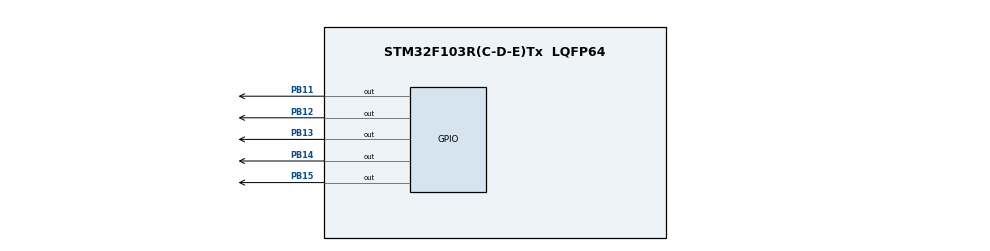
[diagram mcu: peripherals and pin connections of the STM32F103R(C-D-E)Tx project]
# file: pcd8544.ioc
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Mcu.Family=STM32F1
Mcu.Name=STM32F103R(C-D-E)Tx
Mcu.Package=LQFP64
NVIC.PriorityGroup=NVIC_PRIORITYGROUP_4
PB11.GPIO_Speed=GPIO_SPEED_FREQ_HIGH
PB11.Signal=GPIO_Output
PB12.GPIO_Speed=GPIO_SPEED_FREQ_HIGH
PB12.Signal=GPIO_Output
PB13.GPIO_Speed=GPIO_SPEED_FREQ_HIGH
PB13.Signal=GPIO_Output
PB14.GPIO_Speed=GPIO_SPEED_FREQ_HIGH
PB14.Signal=GPIO_Output
PB15.GPIO_Speed=GPIO_SPEED_FREQ_HIGH
PB15.Signal=GPIO_Output
ProjectManager.HeapSize=0x200
ProjectManager.StackSize=0x400
ProjectManager.TargetToolchain=EWARM
RCC.APB1Freq_Value=8000000
RCC.APB2Freq_Value=8000000
board=pcd8544

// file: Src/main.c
/**
  ******************************************************************************
  * File Name          : main.c
  * Description        : Main program body
  ******************************************************************************
  ** This notice applies to any and all portions of this file
  * that are not between comment pairs USER CODE BEGIN and
  * USER CODE END. Other portions of this file, whether
  * inserted by the user or by software development tools
  * are owned by their respective copyright owners.
  *
  * COPYRIGHT(c) 2017 STMicroelectronics
  *
  * Redistribution and use in source and binary forms, with or without modification,
  * are permitted provided that the following conditions are met:
  *   1. Redistributions of source code must retain the above copyright notice,
  *      this list of conditions and the following disclaimer.
  *   2. Redistributions in binary form must reproduce the above copyright notice,
  *      this list of conditions and the following disclaimer in the documentation
  *      and/or other materials provided with the distribution.
  *   3. Neither the name of STMicroelectronics nor the names of its contributors
  *      may be used to endorse or promote products derived from this software
  *      without specific prior written permission.
  *
  * THIS SOFTWARE IS PROVIDED BY THE COPYRIGHT HOLDERS AND CONTRIBUTORS "AS IS"
  * AND ANY EXPRESS OR IMPLIED WARRANTIES, INCLUDING, BUT NOT LIMITED TO, THE
  * IMPLIED WARRANTIES OF MERCHANTABILITY AND FITNESS FOR A PARTICULAR PURPOSE ARE
  * DISCLAIMED. IN NO EVENT SHALL THE COPYRIGHT HOLDER OR CONTRIBUTORS BE LIABLE
  * FOR ANY DIRECT, INDIRECT, INCIDENTAL, SPECIAL, EXEMPLARY, OR CONSEQUENTIAL
  * DAMAGES (INCLUDING, BUT NOT LIMITED TO, PROCUREMENT OF SUBSTITUTE GOODS OR
  * SERVICES; LOSS OF USE, DATA, OR PROFITS; OR BUSINESS INTERRUPTION) HOWEVER
  * CAUSED AND ON ANY THEORY OF LIABILITY, WHETHER IN CONTRACT, STRICT LIABILITY,
  * OR TORT (INCLUDING NEGLIGENCE OR OTHERWISE) ARISING IN ANY WAY OUT OF THE USE
  * OF THIS SOFTWARE, EVEN IF ADVISED OF THE POSSIBILITY OF SUCH DAMAGE.
  *
  ******************************************************************************
  */
#include "main.h"
#include "stm32f1xx_hal.h"
#include "lcd/pcd8544.h"
#include "lcd/Graphic.h"
#include "lcd/AF12x16.h"
#include "lcd/AF9x10.h"
#include "lcd/AF9x11.h"
#include "lcd/f10x20.h"
#include "lcd/f9x14.h"
#include "lcd/f5x7.h"
#include "lcd/Font.h"

/* USER CODE BEGIN PV */
/* Private variables ---------------------------------------------------------*/

/* USER CODE END PV */

void SystemClock_Config(void);
static void MX_GPIO_Init(void);

/* USER CODE BEGIN PFP */
/* Private function prototypes -----------------------------------------------*/

/* USER CODE END PFP */

int main(void)
{

  /* MCU Configuration----------------------------------------------------------*/

  /* Reset of all peripherals, Initializes the Flash interface and the Systick. */
  HAL_Init();

  /* Configure the system clock */
  SystemClock_Config();

  /* Initialize all configured peripherals */
  MX_GPIO_Init();

LcdInitialise();
LcdClear();
gotoXY(1,1);
SetLetter(P_LETTER);
  SetFgColor(1);
  SetBkColor(0);
  LcdFont(AF9x10);
  TextBox(0,0,80,40,"��� ����",ALINE_CENTER|BORDER_FILL);
  PCD8544_Puts("Discovery", PCD8544_Pixel_Set, PCD8544_FontSize_5x7);
 PCD8544_Refresh();
  while (1)
  {
  /* USER CODE END WHILE */

  }

}

/** System Clock Configuration
*/
void SystemClock_Config(void)
{

  RCC_OscInitTypeDef RCC_OscInitStruct;
  RCC_ClkInitTypeDef RCC_ClkInitStruct;

    /**Initializes the CPU, AHB and APB busses clocks
    */
  RCC_OscInitStruct.OscillatorType = RCC_OSCILLATORTYPE_HSI;
  RCC_OscInitStruct.HSIState = RCC_HSI_ON;
  RCC_OscInitStruct.HSICalibrationValue = 16;
  RCC_OscInitStruct.PLL.PLLState = RCC_PLL_NONE;
  if (HAL_RCC_OscConfig(&RCC_OscInitStruct) != HAL_OK)
  {
    _Error_Handler(__FILE__, __LINE__);
  }

    /**Initializes the CPU, AHB and APB busses clocks
    */
  RCC_ClkInitStruct.ClockType = RCC_CLOCKTYPE_HCLK|RCC_CLOCKTYPE_SYSCLK
                              |RCC_CLOCKTYPE_PCLK1|RCC_CLOCKTYPE_PCLK2;
  RCC_ClkInitStruct.SYSCLKSource = RCC_SYSCLKSOURCE_HSI;
  RCC_ClkInitStruct.AHBCLKDivider = RCC_SYSCLK_DIV1;
  RCC_ClkInitStruct.APB1CLKDivider = RCC_HCLK_DIV1;
  RCC_ClkInitStruct.APB2CLKDivider = RCC_HCLK_DIV1;

  if (HAL_RCC_ClockConfig(&RCC_ClkInitStruct, FLASH_LATENCY_0) != HAL_OK)
  {
    _Error_Handler(__FILE__, __LINE__);
  }

    /**Configure the Systick interrupt time
    */
  HAL_SYSTICK_Config(HAL_RCC_GetHCLKFreq()/1000);

    /**Configure the Systick
    */
  HAL_SYSTICK_CLKSourceConfig(SYSTICK_CLKSOURCE_HCLK);

  /* SysTick_IRQn interrupt configuration */
  HAL_NVIC_SetPriority(SysTick_IRQn, 0, 0);
}

/** Configure pins as
        * Analog
        * Input
        * Output
        * EVENT_OUT
        * EXTI
*/
static void MX_GPIO_Init(void)
{

  GPIO_InitTypeDef GPIO_InitStruct;

  /* GPIO Ports Clock Enable */
  __HAL_RCC_GPIOC_CLK_ENABLE();

  /*Configure GPIO pin Output Level */
  HAL_GPIO_WritePin(GPIOC, GPIO_PIN_0|GPIO_PIN_1|GPIO_PIN_2|GPIO_PIN_3
                          |GPIO_PIN_4, GPIO_PIN_RESET);

  /*Configure GPIO pins : PB11 PB12 PB13 PB14
                           PB15 */
  GPIO_InitStruct.Pin = GPIO_PIN_0|GPIO_PIN_1|GPIO_PIN_2|GPIO_PIN_3
                          |GPIO_PIN_4;
  GPIO_InitStruct.Mode = GPIO_MODE_OUTPUT_PP;
  GPIO_InitStruct.Speed = GPIO_SPEED_FREQ_HIGH;
  HAL_GPIO_Init(GPIOC, &GPIO_InitStruct);

}

void _Error_Handler(char * file, int line)
{
  while(1)
  {
  }
}

/************************ (C) COPYRIGHT STMicroelectronics *****END OF FILE****/
